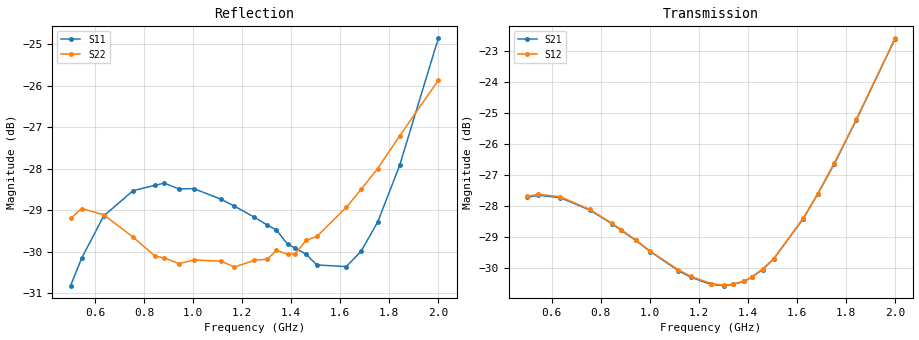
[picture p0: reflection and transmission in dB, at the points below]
!Agilent Technologies,E8363B,SG43030131,A.07.50.48
!Agilent E8363B: A.07.50.48
!Date: Wednesday, October 22, 2025 02:10:35
!Correction: S11(Full 2 Port(1,2))
!S21(Full 2 Port(1,2))
!S12(Full 2 Port(1,2))
!S22(Full 2 Port(1,2))
!S2P File: Measurements: S11, S21, S12, S22:
# Hz S  dB  R 50
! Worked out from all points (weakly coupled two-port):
!   201 points, 500 MHz to 2 GHz, reference 50 ohm
!   highest |S21| = -22.61 dB at 2 GHz (marker M1); lowest = -30.6 dB at 1.302 GHz (marker M2)
!   lowest |S11| = -30.8 dB at 500 MHz (marker M3), VSWR 1.06, Z = 49.3 + j2.77 ohm
!   |S11| at or under -10 dB: start of sweep to end of sweep
!   |S22| runs from -30.4 to -25.9 dB; largest |S21 - S12| = 0.00028
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5e8  -30.82 102.8  -27.72 -39.9  -27.69 -39.9  -29.20 161.2
5.45e8  -30.16 91.8  -27.65 -49.4  -27.62 -49.4  -28.96 152.4
6.35e8  -29.14 70.6  -27.73 -67.0  -27.70 -67.1  -29.11 135.2
7.55e8  -28.53 47.6  -28.13 -88.0  -28.11 -88.2  -29.65 113.0
8.45e8  -28.40 31.6  -28.57 -102.0  -28.55 -102.2  -30.11 96.2
8.825e8  -28.35 25.9  -28.78 -107.5  -28.76 -107.6  -30.15 89.2
9.425e8  -28.49 15.9  -29.11 -115.5  -29.09 -115.7  -30.29 78.7
1.0025e9  -28.48 5.9  -29.47 -122.9  -29.46 -123.0  -30.20 69.0
1.115e9  -28.74 -11.9  -30.08 -134.6  -30.05 -134.8  -30.23 52.5
1.1675e9  -28.90 -21.1  -30.30 -139.3  -30.27 -139.3  -30.37 44.5
1.25e9  -29.17 -34.6  -30.53 -145.4  -30.50 -145.6  -30.21 33.1
1.3025e9  -29.36 -44.9  -30.57 -148.8  -30.56 -148.9  -30.18 24.9
1.34e9  -29.48 -51.6  -30.53 -150.9  -30.52 -151.1  -29.97 20.0
1.385e9  -29.82 -61.0  -30.43 -153.4  -30.42 -153.5  -30.06 14.2
1.415e9  -29.91 -68.0  -30.30 -155.0  -30.29 -155.2  -30.06 8.9
1.46e9  -30.06 -78.0  -30.05 -157.4  -30.03 -157.6  -29.73 1.8
1.505e9  -30.32 -89.4  -29.71 -160.0  -29.70 -160.0  -29.63 -4.3
1.625e9  -30.36 -123.6  -28.42 -168.0  -28.40 -168.0  -28.93 -23.0
1.685e9  -29.99 -142.5  -27.61 -172.9  -27.60 -172.9  -28.50 -33.3
1.7525e9  -29.29 -164.2  -26.64 -179.3  -26.61 -179.4  -28.00 -44.3
1.8425e9  -27.92 167.5  -25.22 170.8  -25.20 170.7  -27.21 -59.5
2e9  -24.86 122.5  -22.61 149.5  -22.59 149.4  -25.87 -89.0
